VERSION 5.7 ;
BUSBITCHARS "[]" ;
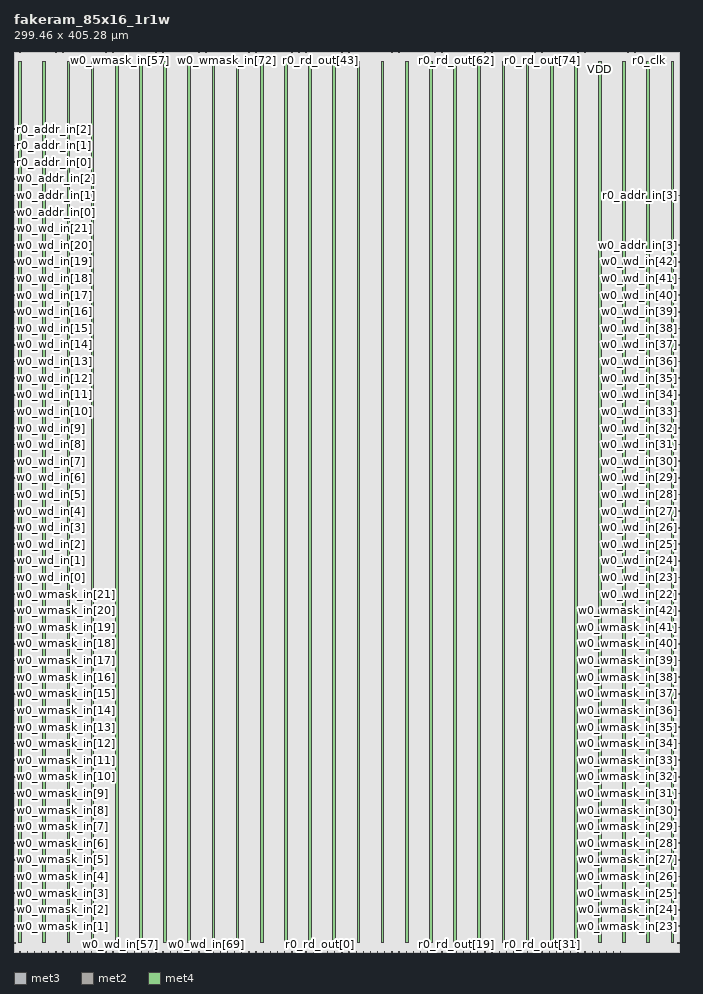
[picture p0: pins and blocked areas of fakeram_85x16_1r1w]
MACRO fakeram_85x16_1r1w
  FOREIGN fakeram_85x16_1r1w 0 0 ;
  SYMMETRY X Y R90 ;
  SIZE 299.460 BY 405.280 ;
  CLASS BLOCK ;
  PIN w0_wmask_in[0]
    DIRECTION INPUT ;
    USE SIGNAL ;
    SHAPE ABUTMENT ;
    PORT
      LAYER met3 ;
      RECT 0.000 3.930 0.900 4.230 ;
    END
  END w0_wmask_in[0]
  PIN w0_wmask_in[1]
    DIRECTION INPUT ;
    USE SIGNAL ;
    SHAPE ABUTMENT ;
    PORT
      LAYER met3 ;
      RECT 0.000 11.410 0.900 11.710 ;
    END
  END w0_wmask_in[1]
  PIN w0_wmask_in[2]
    DIRECTION INPUT ;
    USE SIGNAL ;
    SHAPE ABUTMENT ;
    PORT
      LAYER met3 ;
      RECT 0.000 18.890 0.900 19.190 ;
    END
  END w0_wmask_in[2]
  PIN w0_wmask_in[3]
    DIRECTION INPUT ;
    USE SIGNAL ;
    SHAPE ABUTMENT ;
    PORT
      LAYER met3 ;
      RECT 0.000 26.370 0.900 26.670 ;
    END
  END w0_wmask_in[3]
  PIN w0_wmask_in[4]
    DIRECTION INPUT ;
    USE SIGNAL ;
    SHAPE ABUTMENT ;
    PORT
      LAYER met3 ;
      RECT 0.000 33.850 0.900 34.150 ;
    END
  END w0_wmask_in[4]
  PIN w0_wmask_in[5]
    DIRECTION INPUT ;
    USE SIGNAL ;
    SHAPE ABUTMENT ;
    PORT
      LAYER met3 ;
      RECT 0.000 41.330 0.900 41.630 ;
    END
  END w0_wmask_in[5]
  PIN w0_wmask_in[6]
    DIRECTION INPUT ;
    USE SIGNAL ;
    SHAPE ABUTMENT ;
    PORT
      LAYER met3 ;
      RECT 0.000 48.810 0.900 49.110 ;
    END
  END w0_wmask_in[6]
  PIN w0_wmask_in[7]
    DIRECTION INPUT ;
    USE SIGNAL ;
    SHAPE ABUTMENT ;
    PORT
      LAYER met3 ;
      RECT 0.000 56.290 0.900 56.590 ;
    END
  END w0_wmask_in[7]
  PIN w0_wmask_in[8]
    DIRECTION INPUT ;
    USE SIGNAL ;
    SHAPE ABUTMENT ;
    PORT
      LAYER met3 ;
      RECT 0.000 63.770 0.900 64.070 ;
    END
  END w0_wmask_in[8]
  PIN w0_wmask_in[9]
    DIRECTION INPUT ;
    USE SIGNAL ;
    SHAPE ABUTMENT ;
    PORT
      LAYER met3 ;
      RECT 0.000 71.250 0.900 71.550 ;
    END
  END w0_wmask_in[9]
  PIN w0_wmask_in[10]
    DIRECTION INPUT ;
    USE SIGNAL ;
    SHAPE ABUTMENT ;
    PORT
      LAYER met3 ;
      RECT 0.000 78.730 0.900 79.030 ;
    END
  END w0_wmask_in[10]
  PIN w0_wmask_in[11]
    DIRECTION INPUT ;
    USE SIGNAL ;
    SHAPE ABUTMENT ;
    PORT
      LAYER met3 ;
      RECT 0.000 86.210 0.900 86.510 ;
    END
  END w0_wmask_in[11]
  PIN w0_wmask_in[12]
    DIRECTION INPUT ;
    USE SIGNAL ;
    SHAPE ABUTMENT ;
    PORT
      LAYER met3 ;
      RECT 0.000 93.690 0.900 93.990 ;
    END
  END w0_wmask_in[12]
  PIN w0_wmask_in[13]
    DIRECTION INPUT ;
    USE SIGNAL ;
    SHAPE ABUTMENT ;
    PORT
      LAYER met3 ;
      RECT 0.000 101.170 0.900 101.470 ;
    END
  END w0_wmask_in[13]
  PIN w0_wmask_in[14]
    DIRECTION INPUT ;
    USE SIGNAL ;
    SHAPE ABUTMENT ;
    PORT
      LAYER met3 ;
      RECT 0.000 108.650 0.900 108.950 ;
    END
  END w0_wmask_in[14]
  PIN w0_wmask_in[15]
    DIRECTION INPUT ;
    USE SIGNAL ;
    SHAPE ABUTMENT ;
    PORT
      LAYER met3 ;
      RECT 0.000 116.130 0.900 116.430 ;
    END
  END w0_wmask_in[15]
  PIN w0_wmask_in[16]
    DIRECTION INPUT ;
    USE SIGNAL ;
    SHAPE ABUTMENT ;
    PORT
      LAYER met3 ;
      RECT 0.000 123.610 0.900 123.910 ;
    END
  END w0_wmask_in[16]
  PIN w0_wmask_in[17]
    DIRECTION INPUT ;
    USE SIGNAL ;
    SHAPE ABUTMENT ;
    PORT
      LAYER met3 ;
      RECT 0.000 131.090 0.900 131.390 ;
    END
  END w0_wmask_in[17]
  PIN w0_wmask_in[18]
    DIRECTION INPUT ;
    USE SIGNAL ;
    SHAPE ABUTMENT ;
    PORT
      LAYER met3 ;
      RECT 0.000 138.570 0.900 138.870 ;
    END
  END w0_wmask_in[18]
  PIN w0_wmask_in[19]
    DIRECTION INPUT ;
    USE SIGNAL ;
    SHAPE ABUTMENT ;
    PORT
      LAYER met3 ;
      RECT 0.000 146.050 0.900 146.350 ;
    END
  END w0_wmask_in[19]
  PIN w0_wmask_in[20]
    DIRECTION INPUT ;
    USE SIGNAL ;
    SHAPE ABUTMENT ;
    PORT
      LAYER met3 ;
      RECT 0.000 153.530 0.900 153.830 ;
    END
  END w0_wmask_in[20]
  PIN w0_wmask_in[21]
    DIRECTION INPUT ;
    USE SIGNAL ;
    SHAPE ABUTMENT ;
    PORT
      LAYER met3 ;
      RECT 0.000 161.010 0.900 161.310 ;
    END
  END w0_wmask_in[21]
  PIN w0_wmask_in[22]
    DIRECTION INPUT ;
    USE SIGNAL ;
    SHAPE ABUTMENT ;
    PORT
      LAYER met3 ;
      RECT 298.560 3.930 299.460 4.230 ;
    END
  END w0_wmask_in[22]
  PIN w0_wmask_in[23]
    DIRECTION INPUT ;
    USE SIGNAL ;
    SHAPE ABUTMENT ;
    PORT
      LAYER met3 ;
      RECT 298.560 11.410 299.460 11.710 ;
    END
  END w0_wmask_in[23]
  PIN w0_wmask_in[24]
    DIRECTION INPUT ;
    USE SIGNAL ;
    SHAPE ABUTMENT ;
    PORT
      LAYER met3 ;
      RECT 298.560 18.890 299.460 19.190 ;
    END
  END w0_wmask_in[24]
  PIN w0_wmask_in[25]
    DIRECTION INPUT ;
    USE SIGNAL ;
    SHAPE ABUTMENT ;
    PORT
      LAYER met3 ;
      RECT 298.560 26.370 299.460 26.670 ;
    END
  END w0_wmask_in[25]
  PIN w0_wmask_in[26]
    DIRECTION INPUT ;
    USE SIGNAL ;
    SHAPE ABUTMENT ;
    PORT
      LAYER met3 ;
      RECT 298.560 33.850 299.460 34.150 ;
    END
  END w0_wmask_in[26]
  PIN w0_wmask_in[27]
    DIRECTION INPUT ;
    USE SIGNAL ;
    SHAPE ABUTMENT ;
    PORT
      LAYER met3 ;
      RECT 298.560 41.330 299.460 41.630 ;
    END
  END w0_wmask_in[27]
  PIN w0_wmask_in[28]
    DIRECTION INPUT ;
    USE SIGNAL ;
    SHAPE ABUTMENT ;
    PORT
      LAYER met3 ;
      RECT 298.560 48.810 299.460 49.110 ;
    END
  END w0_wmask_in[28]
  PIN w0_wmask_in[29]
    DIRECTION INPUT ;
    USE SIGNAL ;
    SHAPE ABUTMENT ;
    PORT
      LAYER met3 ;
      RECT 298.560 56.290 299.460 56.590 ;
    END
  END w0_wmask_in[29]
  PIN w0_wmask_in[30]
    DIRECTION INPUT ;
    USE SIGNAL ;
    SHAPE ABUTMENT ;
    PORT
      LAYER met3 ;
      RECT 298.560 63.770 299.460 64.070 ;
    END
  END w0_wmask_in[30]
  PIN w0_wmask_in[31]
    DIRECTION INPUT ;
    USE SIGNAL ;
    SHAPE ABUTMENT ;
    PORT
      LAYER met3 ;
      RECT 298.560 71.250 299.460 71.550 ;
    END
  END w0_wmask_in[31]
  PIN w0_wmask_in[32]
    DIRECTION INPUT ;
    USE SIGNAL ;
    SHAPE ABUTMENT ;
    PORT
      LAYER met3 ;
      RECT 298.560 78.730 299.460 79.030 ;
    END
  END w0_wmask_in[32]
  PIN w0_wmask_in[33]
    DIRECTION INPUT ;
    USE SIGNAL ;
    SHAPE ABUTMENT ;
    PORT
      LAYER met3 ;
      RECT 298.560 86.210 299.460 86.510 ;
    END
  END w0_wmask_in[33]
  PIN w0_wmask_in[34]
    DIRECTION INPUT ;
    USE SIGNAL ;
    SHAPE ABUTMENT ;
    PORT
      LAYER met3 ;
      RECT 298.560 93.690 299.460 93.990 ;
    END
  END w0_wmask_in[34]
  PIN w0_wmask_in[35]
    DIRECTION INPUT ;
    USE SIGNAL ;
    SHAPE ABUTMENT ;
    PORT
      LAYER met3 ;
      RECT 298.560 101.170 299.460 101.470 ;
    END
  END w0_wmask_in[35]
  PIN w0_wmask_in[36]
    DIRECTION INPUT ;
    USE SIGNAL ;
    SHAPE ABUTMENT ;
    PORT
      LAYER met3 ;
      RECT 298.560 108.650 299.460 108.950 ;
    END
  END w0_wmask_in[36]
  PIN w0_wmask_in[37]
    DIRECTION INPUT ;
    USE SIGNAL ;
    SHAPE ABUTMENT ;
    PORT
      LAYER met3 ;
      RECT 298.560 116.130 299.460 116.430 ;
    END
  END w0_wmask_in[37]
  PIN w0_wmask_in[38]
    DIRECTION INPUT ;
    USE SIGNAL ;
    SHAPE ABUTMENT ;
    PORT
      LAYER met3 ;
      RECT 298.560 123.610 299.460 123.910 ;
    END
  END w0_wmask_in[38]
  PIN w0_wmask_in[39]
    DIRECTION INPUT ;
    USE SIGNAL ;
    SHAPE ABUTMENT ;
    PORT
      LAYER met3 ;
      RECT 298.560 131.090 299.460 131.390 ;
    END
  END w0_wmask_in[39]
  PIN w0_wmask_in[40]
    DIRECTION INPUT ;
    USE SIGNAL ;
    SHAPE ABUTMENT ;
    PORT
      LAYER met3 ;
      RECT 298.560 138.570 299.460 138.870 ;
    END
  END w0_wmask_in[40]
  PIN w0_wmask_in[41]
    DIRECTION INPUT ;
    USE SIGNAL ;
    SHAPE ABUTMENT ;
    PORT
      LAYER met3 ;
      RECT 298.560 146.050 299.460 146.350 ;
    END
  END w0_wmask_in[41]
  PIN w0_wmask_in[42]
    DIRECTION INPUT ;
    USE SIGNAL ;
    SHAPE ABUTMENT ;
    PORT
      LAYER met3 ;
      RECT 298.560 153.530 299.460 153.830 ;
    END
  END w0_wmask_in[42]
  PIN w0_wmask_in[43]
    DIRECTION INPUT ;
    USE SIGNAL ;
    SHAPE ABUTMENT ;
    PORT
      LAYER met2 ;
      RECT 2.690 404.860 2.830 405.280 ;
    END
  END w0_wmask_in[43]
  PIN w0_wmask_in[44]
    DIRECTION INPUT ;
    USE SIGNAL ;
    SHAPE ABUTMENT ;
    PORT
      LAYER met2 ;
      RECT 5.910 404.860 6.050 405.280 ;
    END
  END w0_wmask_in[44]
  PIN w0_wmask_in[45]
    DIRECTION INPUT ;
    USE SIGNAL ;
    SHAPE ABUTMENT ;
    PORT
      LAYER met2 ;
      RECT 9.130 404.860 9.270 405.280 ;
    END
  END w0_wmask_in[45]
  PIN w0_wmask_in[46]
    DIRECTION INPUT ;
    USE SIGNAL ;
    SHAPE ABUTMENT ;
    PORT
      LAYER met2 ;
      RECT 12.350 404.860 12.490 405.280 ;
    END
  END w0_wmask_in[46]
  PIN w0_wmask_in[47]
    DIRECTION INPUT ;
    USE SIGNAL ;
    SHAPE ABUTMENT ;
    PORT
      LAYER met2 ;
      RECT 15.570 404.860 15.710 405.280 ;
    END
  END w0_wmask_in[47]
  PIN w0_wmask_in[48]
    DIRECTION INPUT ;
    USE SIGNAL ;
    SHAPE ABUTMENT ;
    PORT
      LAYER met2 ;
      RECT 18.790 404.860 18.930 405.280 ;
    END
  END w0_wmask_in[48]
  PIN w0_wmask_in[49]
    DIRECTION INPUT ;
    USE SIGNAL ;
    SHAPE ABUTMENT ;
    PORT
      LAYER met2 ;
      RECT 22.010 404.860 22.150 405.280 ;
    END
  END w0_wmask_in[49]
  PIN w0_wmask_in[50]
    DIRECTION INPUT ;
    USE SIGNAL ;
    SHAPE ABUTMENT ;
    PORT
      LAYER met2 ;
      RECT 25.230 404.860 25.370 405.280 ;
    END
  END w0_wmask_in[50]
  PIN w0_wmask_in[51]
    DIRECTION INPUT ;
    USE SIGNAL ;
    SHAPE ABUTMENT ;
    PORT
      LAYER met2 ;
      RECT 28.450 404.860 28.590 405.280 ;
    END
  END w0_wmask_in[51]
  PIN w0_wmask_in[52]
    DIRECTION INPUT ;
    USE SIGNAL ;
    SHAPE ABUTMENT ;
    PORT
      LAYER met2 ;
      RECT 31.670 404.860 31.810 405.280 ;
    END
  END w0_wmask_in[52]
  PIN w0_wmask_in[53]
    DIRECTION INPUT ;
    USE SIGNAL ;
    SHAPE ABUTMENT ;
    PORT
      LAYER met2 ;
      RECT 34.890 404.860 35.030 405.280 ;
    END
  END w0_wmask_in[53]
  PIN w0_wmask_in[54]
    DIRECTION INPUT ;
    USE SIGNAL ;
    SHAPE ABUTMENT ;
    PORT
      LAYER met2 ;
      RECT 38.110 404.860 38.250 405.280 ;
    END
  END w0_wmask_in[54]
  PIN w0_wmask_in[55]
    DIRECTION INPUT ;
    USE SIGNAL ;
    SHAPE ABUTMENT ;
    PORT
      LAYER met2 ;
      RECT 41.330 404.860 41.470 405.280 ;
    END
  END w0_wmask_in[55]
  PIN w0_wmask_in[56]
    DIRECTION INPUT ;
    USE SIGNAL ;
    SHAPE ABUTMENT ;
    PORT
      LAYER met2 ;
      RECT 44.550 404.860 44.690 405.280 ;
    END
  END w0_wmask_in[56]
  PIN w0_wmask_in[57]
    DIRECTION INPUT ;
    USE SIGNAL ;
    SHAPE ABUTMENT ;
    PORT
      LAYER met2 ;
      RECT 47.770 404.860 47.910 405.280 ;
    END
  END w0_wmask_in[57]
  PIN w0_wmask_in[58]
    DIRECTION INPUT ;
    USE SIGNAL ;
    SHAPE ABUTMENT ;
    PORT
      LAYER met2 ;
      RECT 50.990 404.860 51.130 405.280 ;
    END
  END w0_wmask_in[58]
  PIN w0_wmask_in[59]
    DIRECTION INPUT ;
    USE SIGNAL ;
    SHAPE ABUTMENT ;
    PORT
      LAYER met2 ;
      RECT 54.210 404.860 54.350 405.280 ;
    END
  END w0_wmask_in[59]
  PIN w0_wmask_in[60]
    DIRECTION INPUT ;
    USE SIGNAL ;
    SHAPE ABUTMENT ;
    PORT
      LAYER met2 ;
      RECT 57.430 404.860 57.570 405.280 ;
    END
  END w0_wmask_in[60]
  PIN w0_wmask_in[61]
    DIRECTION INPUT ;
    USE SIGNAL ;
    SHAPE ABUTMENT ;
    PORT
      LAYER met2 ;
      RECT 60.650 404.860 60.790 405.280 ;
    END
  END w0_wmask_in[61]
  PIN w0_wmask_in[62]
    DIRECTION INPUT ;
    USE SIGNAL ;
    SHAPE ABUTMENT ;
    PORT
      LAYER met2 ;
      RECT 63.870 404.860 64.010 405.280 ;
    END
  END w0_wmask_in[62]
  PIN w0_wmask_in[63]
    DIRECTION INPUT ;
    USE SIGNAL ;
    SHAPE ABUTMENT ;
    PORT
      LAYER met2 ;
      RECT 67.090 404.860 67.230 405.280 ;
    END
  END w0_wmask_in[63]
  PIN w0_wmask_in[64]
    DIRECTION INPUT ;
    USE SIGNAL ;
    SHAPE ABUTMENT ;
    PORT
      LAYER met2 ;
      RECT 70.310 404.860 70.450 405.280 ;
    END
  END w0_wmask_in[64]
  PIN w0_wmask_in[65]
    DIRECTION INPUT ;
    USE SIGNAL ;
    SHAPE ABUTMENT ;
    PORT
      LAYER met2 ;
      RECT 73.530 404.860 73.670 405.280 ;
    END
  END w0_wmask_in[65]
  PIN w0_wmask_in[66]
    DIRECTION INPUT ;
    USE SIGNAL ;
    SHAPE ABUTMENT ;
    PORT
      LAYER met2 ;
      RECT 76.750 404.860 76.890 405.280 ;
    END
  END w0_wmask_in[66]
  PIN w0_wmask_in[67]
    DIRECTION INPUT ;
    USE SIGNAL ;
    SHAPE ABUTMENT ;
    PORT
      LAYER met2 ;
      RECT 79.970 404.860 80.110 405.280 ;
    END
  END w0_wmask_in[67]
  PIN w0_wmask_in[68]
    DIRECTION INPUT ;
    USE SIGNAL ;
    SHAPE ABUTMENT ;
    PORT
      LAYER met2 ;
      RECT 83.190 404.860 83.330 405.280 ;
    END
  END w0_wmask_in[68]
  PIN w0_wmask_in[69]
    DIRECTION INPUT ;
    USE SIGNAL ;
    SHAPE ABUTMENT ;
    PORT
      LAYER met2 ;
      RECT 86.410 404.860 86.550 405.280 ;
    END
  END w0_wmask_in[69]
  PIN w0_wmask_in[70]
    DIRECTION INPUT ;
    USE SIGNAL ;
    SHAPE ABUTMENT ;
    PORT
      LAYER met2 ;
      RECT 89.630 404.860 89.770 405.280 ;
    END
  END w0_wmask_in[70]
  PIN w0_wmask_in[71]
    DIRECTION INPUT ;
    USE SIGNAL ;
    SHAPE ABUTMENT ;
    PORT
      LAYER met2 ;
      RECT 92.850 404.860 92.990 405.280 ;
    END
  END w0_wmask_in[71]
  PIN w0_wmask_in[72]
    DIRECTION INPUT ;
    USE SIGNAL ;
    SHAPE ABUTMENT ;
    PORT
      LAYER met2 ;
      RECT 96.070 404.860 96.210 405.280 ;
    END
  END w0_wmask_in[72]
  PIN w0_wmask_in[73]
    DIRECTION INPUT ;
    USE SIGNAL ;
    SHAPE ABUTMENT ;
    PORT
      LAYER met2 ;
      RECT 99.290 404.860 99.430 405.280 ;
    END
  END w0_wmask_in[73]
  PIN w0_wmask_in[74]
    DIRECTION INPUT ;
    USE SIGNAL ;
    SHAPE ABUTMENT ;
    PORT
      LAYER met2 ;
      RECT 102.510 404.860 102.650 405.280 ;
    END
  END w0_wmask_in[74]
  PIN w0_wmask_in[75]
    DIRECTION INPUT ;
    USE SIGNAL ;
    SHAPE ABUTMENT ;
    PORT
      LAYER met2 ;
      RECT 105.730 404.860 105.870 405.280 ;
    END
  END w0_wmask_in[75]
  PIN w0_wmask_in[76]
    DIRECTION INPUT ;
    USE SIGNAL ;
    SHAPE ABUTMENT ;
    PORT
      LAYER met2 ;
      RECT 108.950 404.860 109.090 405.280 ;
    END
  END w0_wmask_in[76]
  PIN w0_wmask_in[77]
    DIRECTION INPUT ;
    USE SIGNAL ;
    SHAPE ABUTMENT ;
    PORT
      LAYER met2 ;
      RECT 112.170 404.860 112.310 405.280 ;
    END
  END w0_wmask_in[77]
  PIN w0_wmask_in[78]
    DIRECTION INPUT ;
    USE SIGNAL ;
    SHAPE ABUTMENT ;
    PORT
      LAYER met2 ;
      RECT 115.390 404.860 115.530 405.280 ;
    END
  END w0_wmask_in[78]
  PIN w0_wmask_in[79]
    DIRECTION INPUT ;
    USE SIGNAL ;
    SHAPE ABUTMENT ;
    PORT
      LAYER met2 ;
      RECT 118.610 404.860 118.750 405.280 ;
    END
  END w0_wmask_in[79]
  PIN w0_wmask_in[80]
    DIRECTION INPUT ;
    USE SIGNAL ;
    SHAPE ABUTMENT ;
    PORT
      LAYER met2 ;
      RECT 121.830 404.860 121.970 405.280 ;
    END
  END w0_wmask_in[80]
  PIN w0_wmask_in[81]
    DIRECTION INPUT ;
    USE SIGNAL ;
    SHAPE ABUTMENT ;
    PORT
      LAYER met2 ;
      RECT 125.050 404.860 125.190 405.280 ;
    END
  END w0_wmask_in[81]
  PIN w0_wmask_in[82]
    DIRECTION INPUT ;
    USE SIGNAL ;
    SHAPE ABUTMENT ;
    PORT
      LAYER met2 ;
      RECT 128.270 404.860 128.410 405.280 ;
    END
  END w0_wmask_in[82]
  PIN w0_wmask_in[83]
    DIRECTION INPUT ;
    USE SIGNAL ;
    SHAPE ABUTMENT ;
    PORT
      LAYER met2 ;
      RECT 131.490 404.860 131.630 405.280 ;
    END
  END w0_wmask_in[83]
  PIN w0_wmask_in[84]
    DIRECTION INPUT ;
    USE SIGNAL ;
    SHAPE ABUTMENT ;
    PORT
      LAYER met2 ;
      RECT 134.710 404.860 134.850 405.280 ;
    END
  END w0_wmask_in[84]
  PIN w0_wd_in[0]
    DIRECTION INPUT ;
    USE SIGNAL ;
    SHAPE ABUTMENT ;
    PORT
      LAYER met3 ;
      RECT 0.000 168.490 0.900 168.790 ;
    END
  END w0_wd_in[0]
  PIN w0_wd_in[1]
    DIRECTION INPUT ;
    USE SIGNAL ;
    SHAPE ABUTMENT ;
    PORT
      LAYER met3 ;
      RECT 0.000 175.970 0.900 176.270 ;
    END
  END w0_wd_in[1]
  PIN w0_wd_in[2]
    DIRECTION INPUT ;
    USE SIGNAL ;
    SHAPE ABUTMENT ;
    PORT
      LAYER met3 ;
      RECT 0.000 183.450 0.900 183.750 ;
    END
  END w0_wd_in[2]
  PIN w0_wd_in[3]
    DIRECTION INPUT ;
    USE SIGNAL ;
    SHAPE ABUTMENT ;
    PORT
      LAYER met3 ;
      RECT 0.000 190.930 0.900 191.230 ;
    END
  END w0_wd_in[3]
  PIN w0_wd_in[4]
    DIRECTION INPUT ;
    USE SIGNAL ;
    SHAPE ABUTMENT ;
    PORT
      LAYER met3 ;
      RECT 0.000 198.410 0.900 198.710 ;
    END
  END w0_wd_in[4]
  PIN w0_wd_in[5]
    DIRECTION INPUT ;
    USE SIGNAL ;
    SHAPE ABUTMENT ;
    PORT
      LAYER met3 ;
      RECT 0.000 205.890 0.900 206.190 ;
    END
  END w0_wd_in[5]
  PIN w0_wd_in[6]
    DIRECTION INPUT ;
    USE SIGNAL ;
    SHAPE ABUTMENT ;
    PORT
      LAYER met3 ;
      RECT 0.000 213.370 0.900 213.670 ;
    END
  END w0_wd_in[6]
  PIN w0_wd_in[7]
    DIRECTION INPUT ;
    USE SIGNAL ;
    SHAPE ABUTMENT ;
    PORT
      LAYER met3 ;
      RECT 0.000 220.850 0.900 221.150 ;
    END
  END w0_wd_in[7]
  PIN w0_wd_in[8]
    DIRECTION INPUT ;
    USE SIGNAL ;
    SHAPE ABUTMENT ;
    PORT
      LAYER met3 ;
      RECT 0.000 228.330 0.900 228.630 ;
    END
  END w0_wd_in[8]
  PIN w0_wd_in[9]
    DIRECTION INPUT ;
    USE SIGNAL ;
    SHAPE ABUTMENT ;
    PORT
      LAYER met3 ;
      RECT 0.000 235.810 0.900 236.110 ;
    END
  END w0_wd_in[9]
  PIN w0_wd_in[10]
    DIRECTION INPUT ;
    USE SIGNAL ;
    SHAPE ABUTMENT ;
    PORT
      LAYER met3 ;
      RECT 0.000 243.290 0.900 243.590 ;
    END
  END w0_wd_in[10]
  PIN w0_wd_in[11]
    DIRECTION INPUT ;
    USE SIGNAL ;
    SHAPE ABUTMENT ;
    PORT
      LAYER met3 ;
      RECT 0.000 250.770 0.900 251.070 ;
    END
  END w0_wd_in[11]
  PIN w0_wd_in[12]
    DIRECTION INPUT ;
    USE SIGNAL ;
    SHAPE ABUTMENT ;
    PORT
      LAYER met3 ;
      RECT 0.000 258.250 0.900 258.550 ;
    END
  END w0_wd_in[12]
  PIN w0_wd_in[13]
    DIRECTION INPUT ;
    USE SIGNAL ;
    SHAPE ABUTMENT ;
    PORT
      LAYER met3 ;
      RECT 0.000 265.730 0.900 266.030 ;
    END
  END w0_wd_in[13]
  PIN w0_wd_in[14]
    DIRECTION INPUT ;
    USE SIGNAL ;
    SHAPE ABUTMENT ;
    PORT
      LAYER met3 ;
      RECT 0.000 273.210 0.900 273.510 ;
    END
  END w0_wd_in[14]
  PIN w0_wd_in[15]
    DIRECTION INPUT ;
    USE SIGNAL ;
    SHAPE ABUTMENT ;
    PORT
      LAYER met3 ;
      RECT 0.000 280.690 0.900 280.990 ;
    END
  END w0_wd_in[15]
  PIN w0_wd_in[16]
    DIRECTION INPUT ;
    USE SIGNAL ;
    SHAPE ABUTMENT ;
    PORT
      LAYER met3 ;
      RECT 0.000 288.170 0.900 288.470 ;
    END
  END w0_wd_in[16]
  PIN w0_wd_in[17]
    DIRECTION INPUT ;
    USE SIGNAL ;
    SHAPE ABUTMENT ;
    PORT
      LAYER met3 ;
      RECT 0.000 295.650 0.900 295.950 ;
    END
  END w0_wd_in[17]
  PIN w0_wd_in[18]
    DIRECTION INPUT ;
    USE SIGNAL ;
    SHAPE ABUTMENT ;
    PORT
      LAYER met3 ;
      RECT 0.000 303.130 0.900 303.430 ;
    END
  END w0_wd_in[18]
  PIN w0_wd_in[19]
    DIRECTION INPUT ;
    USE SIGNAL ;
    SHAPE ABUTMENT ;
    PORT
      LAYER met3 ;
      RECT 0.000 310.610 0.900 310.910 ;
    END
  END w0_wd_in[19]
  PIN w0_wd_in[20]
    DIRECTION INPUT ;
    USE SIGNAL ;
    SHAPE ABUTMENT ;
    PORT
      LAYER met3 ;
      RECT 0.000 318.090 0.900 318.390 ;
    END
  END w0_wd_in[20]
  PIN w0_wd_in[21]
    DIRECTION INPUT ;
    USE SIGNAL ;
    SHAPE ABUTMENT ;
    PORT
      LAYER met3 ;
      RECT 0.000 325.570 0.900 325.870 ;
    END
  END w0_wd_in[21]
  PIN w0_wd_in[22]
    DIRECTION INPUT ;
    USE SIGNAL ;
    SHAPE ABUTMENT ;
    PORT
      LAYER met3 ;
      RECT 298.560 161.010 299.460 161.310 ;
    END
  END w0_wd_in[22]
  PIN w0_wd_in[23]
    DIRECTION INPUT ;
    USE SIGNAL ;
    SHAPE ABUTMENT ;
    PORT
      LAYER met3 ;
      RECT 298.560 168.490 299.460 168.790 ;
    END
  END w0_wd_in[23]
  PIN w0_wd_in[24]
    DIRECTION INPUT ;
    USE SIGNAL ;
    SHAPE ABUTMENT ;
    PORT
      LAYER met3 ;
      RECT 298.560 175.970 299.460 176.270 ;
    END
  END w0_wd_in[24]
  PIN w0_wd_in[25]
    DIRECTION INPUT ;
    USE SIGNAL ;
    SHAPE ABUTMENT ;
    PORT
      LAYER met3 ;
      RECT 298.560 183.450 299.460 183.750 ;
    END
  END w0_wd_in[25]
  PIN w0_wd_in[26]
    DIRECTION INPUT ;
    USE SIGNAL ;
    SHAPE ABUTMENT ;
    PORT
      LAYER met3 ;
      RECT 298.560 190.930 299.460 191.230 ;
    END
  END w0_wd_in[26]
  PIN w0_wd_in[27]
    DIRECTION INPUT ;
    USE SIGNAL ;
    SHAPE ABUTMENT ;
    PORT
      LAYER met3 ;
      RECT 298.560 198.410 299.460 198.710 ;
    END
  END w0_wd_in[27]
  PIN w0_wd_in[28]
    DIRECTION INPUT ;
    USE SIGNAL ;
    SHAPE ABUTMENT ;
    PORT
      LAYER met3 ;
      RECT 298.560 205.890 299.460 206.190 ;
    END
  END w0_wd_in[28]
  PIN w0_wd_in[29]
    DIRECTION INPUT ;
    USE SIGNAL ;
    SHAPE ABUTMENT ;
    PORT
      LAYER met3 ;
      RECT 298.560 213.370 299.460 213.670 ;
    END
  END w0_wd_in[29]
  PIN w0_wd_in[30]
    DIRECTION INPUT ;
    USE SIGNAL ;
    SHAPE ABUTMENT ;
    PORT
      LAYER met3 ;
      RECT 298.560 220.850 299.460 221.150 ;
    END
  END w0_wd_in[30]
  PIN w0_wd_in[31]
    DIRECTION INPUT ;
    USE SIGNAL ;
    SHAPE ABUTMENT ;
    PORT
      LAYER met3 ;
      RECT 298.560 228.330 299.460 228.630 ;
    END
  END w0_wd_in[31]
  PIN w0_wd_in[32]
    DIRECTION INPUT ;
    USE SIGNAL ;
    SHAPE ABUTMENT ;
    PORT
      LAYER met3 ;
      RECT 298.560 235.810 299.460 236.110 ;
    END
  END w0_wd_in[32]
  PIN w0_wd_in[33]
    DIRECTION INPUT ;
    USE SIGNAL ;
    SHAPE ABUTMENT ;
    PORT
      LAYER met3 ;
      RECT 298.560 243.290 299.460 243.590 ;
    END
  END w0_wd_in[33]
  PIN w0_wd_in[34]
    DIRECTION INPUT ;
    USE SIGNAL ;
    SHAPE ABUTMENT ;
    PORT
      LAYER met3 ;
      RECT 298.560 250.770 299.460 251.070 ;
    END
  END w0_wd_in[34]
  PIN w0_wd_in[35]
    DIRECTION INPUT ;
    USE SIGNAL ;
    SHAPE ABUTMENT ;
    PORT
      LAYER met3 ;
      RECT 298.560 258.250 299.460 258.550 ;
    END
  END w0_wd_in[35]
  PIN w0_wd_in[36]
    DIRECTION INPUT ;
    USE SIGNAL ;
    SHAPE ABUTMENT ;
    PORT
      LAYER met3 ;
      RECT 298.560 265.730 299.460 266.030 ;
    END
  END w0_wd_in[36]
  PIN w0_wd_in[37]
    DIRECTION INPUT ;
    USE SIGNAL ;
    SHAPE ABUTMENT ;
    PORT
      LAYER met3 ;
      RECT 298.560 273.210 299.460 273.510 ;
    END
  END w0_wd_in[37]
  PIN w0_wd_in[38]
    DIRECTION INPUT ;
    USE SIGNAL ;
    SHAPE ABUTMENT ;
    PORT
      LAYER met3 ;
      RECT 298.560 280.690 299.460 280.990 ;
    END
  END w0_wd_in[38]
  PIN w0_wd_in[39]
    DIRECTION INPUT ;
    USE SIGNAL ;
    SHAPE ABUTMENT ;
    PORT
      LAYER met3 ;
      RECT 298.560 288.170 299.460 288.470 ;
    END
  END w0_wd_in[39]
  PIN w0_wd_in[40]
    DIRECTION INPUT ;
    USE SIGNAL ;
    SHAPE ABUTMENT ;
    PORT
      LAYER met3 ;
      RECT 298.560 295.650 299.460 295.950 ;
    END
  END w0_wd_in[40]
  PIN w0_wd_in[41]
    DIRECTION INPUT ;
    USE SIGNAL ;
    SHAPE ABUTMENT ;
    PORT
      LAYER met3 ;
      RECT 298.560 303.130 299.460 303.430 ;
    END
  END w0_wd_in[41]
  PIN w0_wd_in[42]
    DIRECTION INPUT ;
    USE SIGNAL ;
    SHAPE ABUTMENT ;
    PORT
      LAYER met3 ;
      RECT 298.560 310.610 299.460 310.910 ;
    END
  END w0_wd_in[42]
  PIN w0_wd_in[43]
    DIRECTION OUTPUT ;
    USE SIGNAL ;
    SHAPE ABUTMENT ;
    PORT
      LAYER met2 ;
      RECT 2.690 0.000 2.830 0.420 ;
    END
  END w0_wd_in[43]
  PIN w0_wd_in[44]
    DIRECTION OUTPUT ;
    USE SIGNAL ;
    SHAPE ABUTMENT ;
    PORT
      LAYER met2 ;
      RECT 5.910 0.000 6.050 0.420 ;
    END
  END w0_wd_in[44]
  PIN w0_wd_in[45]
    DIRECTION OUTPUT ;
    USE SIGNAL ;
    SHAPE ABUTMENT ;
    PORT
      LAYER met2 ;
      RECT 9.130 0.000 9.270 0.420 ;
    END
  END w0_wd_in[45]
  PIN w0_wd_in[46]
    DIRECTION OUTPUT ;
    USE SIGNAL ;
    SHAPE ABUTMENT ;
    PORT
      LAYER met2 ;
      RECT 12.350 0.000 12.490 0.420 ;
    END
  END w0_wd_in[46]
  PIN w0_wd_in[47]
    DIRECTION OUTPUT ;
    USE SIGNAL ;
    SHAPE ABUTMENT ;
    PORT
      LAYER met2 ;
      RECT 15.570 0.000 15.710 0.420 ;
    END
  END w0_wd_in[47]
  PIN w0_wd_in[48]
    DIRECTION OUTPUT ;
    USE SIGNAL ;
    SHAPE ABUTMENT ;
    PORT
      LAYER met2 ;
      RECT 18.790 0.000 18.930 0.420 ;
    END
  END w0_wd_in[48]
  PIN w0_wd_in[49]
    DIRECTION OUTPUT ;
    USE SIGNAL ;
    SHAPE ABUTMENT ;
    PORT
      LAYER met2 ;
      RECT 22.010 0.000 22.150 0.420 ;
    END
  END w0_wd_in[49]
  PIN w0_wd_in[50]
    DIRECTION OUTPUT ;
    USE SIGNAL ;
    SHAPE ABUTMENT ;
    PORT
      LAYER met2 ;
      RECT 25.230 0.000 25.370 0.420 ;
    END
  END w0_wd_in[50]
  PIN w0_wd_in[51]
    DIRECTION OUTPUT ;
    USE SIGNAL ;
    SHAPE ABUTMENT ;
    PORT
      LAYER met2 ;
      RECT 28.450 0.000 28.590 0.420 ;
    END
  END w0_wd_in[51]
  PIN w0_wd_in[52]
    DIRECTION OUTPUT ;
    USE SIGNAL ;
    SHAPE ABUTMENT ;
    PORT
      LAYER met2 ;
      RECT 31.670 0.000 31.810 0.420 ;
    END
  END w0_wd_in[52]
  PIN w0_wd_in[53]
    DIRECTION OUTPUT ;
    USE SIGNAL ;
    SHAPE ABUTMENT ;
    PORT
      LAYER met2 ;
      RECT 34.890 0.000 35.030 0.420 ;
    END
  END w0_wd_in[53]
  PIN w0_wd_in[54]
    DIRECTION OUTPUT ;
    USE SIGNAL ;
    SHAPE ABUTMENT ;
    PORT
      LAYER met2 ;
      RECT 38.110 0.000 38.250 0.420 ;
    END
  END w0_wd_in[54]
  PIN w0_wd_in[55]
    DIRECTION OUTPUT ;
    USE SIGNAL ;
    SHAPE ABUTMENT ;
    PORT
      LAYER met2 ;
      RECT 41.330 0.000 41.470 0.420 ;
    END
  END w0_wd_in[55]
  PIN w0_wd_in[56]
    DIRECTION OUTPUT ;
    USE SIGNAL ;
    SHAPE ABUTMENT ;
    PORT
      LAYER met2 ;
      RECT 44.550 0.000 44.690 0.420 ;
    END
  END w0_wd_in[56]
  PIN w0_wd_in[57]
    DIRECTION OUTPUT ;
    USE SIGNAL ;
    SHAPE ABUTMENT ;
    PORT
      LAYER met2 ;
      RECT 47.770 0.000 47.910 0.420 ;
    END
  END w0_wd_in[57]
  PIN w0_wd_in[58]
    DIRECTION OUTPUT ;
    USE SIGNAL ;
    SHAPE ABUTMENT ;
    PORT
      LAYER met2 ;
      RECT 50.990 0.000 51.130 0.420 ;
    END
  END w0_wd_in[58]
  PIN w0_wd_in[59]
    DIRECTION OUTPUT ;
    USE SIGNAL ;
    SHAPE ABUTMENT ;
    PORT
      LAYER met2 ;
      RECT 54.210 0.000 54.350 0.420 ;
    END
  END w0_wd_in[59]
  PIN w0_wd_in[60]
    DIRECTION OUTPUT ;
    USE SIGNAL ;
    SHAPE ABUTMENT ;
    PORT
      LAYER met2 ;
      RECT 57.430 0.000 57.570 0.420 ;
    END
  END w0_wd_in[60]
  PIN w0_wd_in[61]
    DIRECTION OUTPUT ;
    USE SIGNAL ;
    SHAPE ABUTMENT ;
    PORT
      LAYER met2 ;
      RECT 60.650 0.000 60.790 0.420 ;
    END
  END w0_wd_in[61]
  PIN w0_wd_in[62]
    DIRECTION OUTPUT ;
    USE SIGNAL ;
    SHAPE ABUTMENT ;
    PORT
      LAYER met2 ;
      RECT 63.870 0.000 64.010 0.420 ;
    END
  END w0_wd_in[62]
  PIN w0_wd_in[63]
    DIRECTION OUTPUT ;
    USE SIGNAL ;
    SHAPE ABUTMENT ;
    PORT
      LAYER met2 ;
      RECT 67.090 0.000 67.230 0.420 ;
    END
  END w0_wd_in[63]
  PIN w0_wd_in[64]
    DIRECTION OUTPUT ;
    USE SIGNAL ;
    SHAPE ABUTMENT ;
    PORT
      LAYER met2 ;
      RECT 70.310 0.000 70.450 0.420 ;
    END
  END w0_wd_in[64]
  PIN w0_wd_in[65]
    DIRECTION OUTPUT ;
    USE SIGNAL ;
    SHAPE ABUTMENT ;
    PORT
      LAYER met2 ;
      RECT 73.530 0.000 73.670 0.420 ;
    END
  END w0_wd_in[65]
  PIN w0_wd_in[66]
    DIRECTION OUTPUT ;
    USE SIGNAL ;
    SHAPE ABUTMENT ;
    PORT
      LAYER met2 ;
      RECT 76.750 0.000 76.890 0.420 ;
    END
  END w0_wd_in[66]
  PIN w0_wd_in[67]
    DIRECTION OUTPUT ;
    USE SIGNAL ;
    SHAPE ABUTMENT ;
    PORT
      LAYER met2 ;
      RECT 79.970 0.000 80.110 0.420 ;
    END
  END w0_wd_in[67]
  PIN w0_wd_in[68]
    DIRECTION OUTPUT ;
    USE SIGNAL ;
    SHAPE ABUTMENT ;
    PORT
      LAYER met2 ;
      RECT 83.190 0.000 83.330 0.420 ;
    END
  END w0_wd_in[68]
  PIN w0_wd_in[69]
    DIRECTION OUTPUT ;
    USE SIGNAL ;
    SHAPE ABUTMENT ;
    PORT
      LAYER met2 ;
      RECT 86.410 0.000 86.550 0.420 ;
    END
  END w0_wd_in[69]
  PIN w0_wd_in[70]
    DIRECTION OUTPUT ;
    USE SIGNAL ;
    SHAPE ABUTMENT ;
    PORT
      LAYER met2 ;
      RECT 89.630 0.000 89.770 0.420 ;
    END
  END w0_wd_in[70]
  PIN w0_wd_in[71]
    DIRECTION OUTPUT ;
    USE SIGNAL ;
    SHAPE ABUTMENT ;
    PORT
      LAYER met2 ;
      RECT 92.850 0.000 92.990 0.420 ;
    END
  END w0_wd_in[71]
  PIN w0_wd_in[72]
    DIRECTION OUTPUT ;
    USE SIGNAL ;
    SHAPE ABUTMENT ;
    PORT
      LAYER met2 ;
      RECT 96.070 0.000 96.210 0.420 ;
    END
  END w0_wd_in[72]
  PIN w0_wd_in[73]
    DIRECTION OUTPUT ;
    USE SIGNAL ;
    SHAPE ABUTMENT ;
    PORT
      LAYER met2 ;
      RECT 99.290 0.000 99.430 0.420 ;
    END
  END w0_wd_in[73]
  PIN w0_wd_in[74]
    DIRECTION OUTPUT ;
    USE SIGNAL ;
    SHAPE ABUTMENT ;
    PORT
      LAYER met2 ;
      RECT 102.510 0.000 102.650 0.420 ;
    END
  END w0_wd_in[74]
  PIN w0_wd_in[75]
    DIRECTION OUTPUT ;
    USE SIGNAL ;
    SHAPE ABUTMENT ;
    PORT
      LAYER met2 ;
      RECT 105.730 0.000 105.870 0.420 ;
    END
  END w0_wd_in[75]
  PIN w0_wd_in[76]
    DIRECTION OUTPUT ;
    USE SIGNAL ;
    SHAPE ABUTMENT ;
    PORT
      LAYER met2 ;
      RECT 108.950 0.000 109.090 0.420 ;
    END
  END w0_wd_in[76]
  PIN w0_wd_in[77]
    DIRECTION OUTPUT ;
    USE SIGNAL ;
    SHAPE ABUTMENT ;
    PORT
      LAYER met2 ;
      RECT 112.170 0.000 112.310 0.420 ;
    END
  END w0_wd_in[77]
  PIN w0_wd_in[78]
    DIRECTION OUTPUT ;
    USE SIGNAL ;
    SHAPE ABUTMENT ;
    PORT
      LAYER met2 ;
      RECT 115.390 0.000 115.530 0.420 ;
    END
  END w0_wd_in[78]
  PIN w0_wd_in[79]
    DIRECTION OUTPUT ;
    USE SIGNAL ;
    SHAPE ABUTMENT ;
    PORT
      LAYER met2 ;
      RECT 118.610 0.000 118.750 0.420 ;
    END
  END w0_wd_in[79]
  PIN w0_wd_in[80]
    DIRECTION OUTPUT ;
    USE SIGNAL ;
    SHAPE ABUTMENT ;
    PORT
      LAYER met2 ;
      RECT 121.830 0.000 121.970 0.420 ;
    END
  END w0_wd_in[80]
  PIN w0_wd_in[81]
    DIRECTION OUTPUT ;
    USE SIGNAL ;
    SHAPE ABUTMENT ;
    PORT
      LAYER met2 ;
      RECT 125.050 0.000 125.190 0.420 ;
    END
  END w0_wd_in[81]
  PIN w0_wd_in[82]
    DIRECTION OUTPUT ;
    USE SIGNAL ;
    SHAPE ABUTMENT ;
    PORT
      LAYER met2 ;
      RECT 128.270 0.000 128.410 0.420 ;
    END
  END w0_wd_in[82]
  PIN w0_wd_in[83]
    DIRECTION OUTPUT ;
    USE SIGNAL ;
    SHAPE ABUTMENT ;
    PORT
      LAYER met2 ;
      RECT 131.490 0.000 131.630 0.420 ;
    END
  END w0_wd_in[83]
  PIN w0_wd_in[84]
    DIRECTION OUTPUT ;
    USE SIGNAL ;
    SHAPE ABUTMENT ;
    PORT
      LAYER met2 ;
      RECT 134.710 0.000 134.850 0.420 ;
    END
  END w0_wd_in[84]
  PIN r0_rd_out[0]
    DIRECTION OUTPUT ;
    USE SIGNAL ;
    SHAPE ABUTMENT ;
    PORT
      LAYER met2 ;
      RECT 137.930 0.000 138.070 0.420 ;
    END
  END r0_rd_out[0]
  PIN r0_rd_out[1]
    DIRECTION OUTPUT ;
    USE SIGNAL ;
    SHAPE ABUTMENT ;
    PORT
      LAYER met2 ;
      RECT 141.150 0.000 141.290 0.420 ;
    END
  END r0_rd_out[1]
  PIN r0_rd_out[2]
    DIRECTION OUTPUT ;
    USE SIGNAL ;
    SHAPE ABUTMENT ;
    PORT
      LAYER met2 ;
      RECT 144.370 0.000 144.510 0.420 ;
    END
  END r0_rd_out[2]
  PIN r0_rd_out[3]
    DIRECTION OUTPUT ;
    USE SIGNAL ;
    SHAPE ABUTMENT ;
    PORT
      LAYER met2 ;
      RECT 147.590 0.000 147.730 0.420 ;
    END
  END r0_rd_out[3]
  PIN r0_rd_out[4]
    DIRECTION OUTPUT ;
    USE SIGNAL ;
    SHAPE ABUTMENT ;
    PORT
      LAYER met2 ;
      RECT 150.810 0.000 150.950 0.420 ;
    END
  END r0_rd_out[4]
  PIN r0_rd_out[5]
    DIRECTION OUTPUT ;
    USE SIGNAL ;
    SHAPE ABUTMENT ;
    PORT
      LAYER met2 ;
      RECT 154.030 0.000 154.170 0.420 ;
    END
  END r0_rd_out[5]
  PIN r0_rd_out[6]
    DIRECTION OUTPUT ;
    USE SIGNAL ;
    SHAPE ABUTMENT ;
    PORT
      LAYER met2 ;
      RECT 157.250 0.000 157.390 0.420 ;
    END
  END r0_rd_out[6]
  PIN r0_rd_out[7]
    DIRECTION OUTPUT ;
    USE SIGNAL ;
    SHAPE ABUTMENT ;
    PORT
      LAYER met2 ;
      RECT 160.470 0.000 160.610 0.420 ;
    END
  END r0_rd_out[7]
  PIN r0_rd_out[8]
    DIRECTION OUTPUT ;
    USE SIGNAL ;
    SHAPE ABUTMENT ;
    PORT
      LAYER met2 ;
      RECT 163.690 0.000 163.830 0.420 ;
    END
  END r0_rd_out[8]
  PIN r0_rd_out[9]
    DIRECTION OUTPUT ;
    USE SIGNAL ;
    SHAPE ABUTMENT ;
    PORT
      LAYER met2 ;
      RECT 166.910 0.000 167.050 0.420 ;
    END
  END r0_rd_out[9]
  PIN r0_rd_out[10]
    DIRECTION OUTPUT ;
    USE SIGNAL ;
    SHAPE ABUTMENT ;
    PORT
      LAYER met2 ;
      RECT 170.130 0.000 170.270 0.420 ;
    END
  END r0_rd_out[10]
  PIN r0_rd_out[11]
    DIRECTION OUTPUT ;
    USE SIGNAL ;
    SHAPE ABUTMENT ;
    PORT
      LAYER met2 ;
      RECT 173.350 0.000 173.490 0.420 ;
    END
  END r0_rd_out[11]
  PIN r0_rd_out[12]
    DIRECTION OUTPUT ;
    USE SIGNAL ;
    SHAPE ABUTMENT ;
    PORT
      LAYER met2 ;
      RECT 176.570 0.000 176.710 0.420 ;
    END
  END r0_rd_out[12]
  PIN r0_rd_out[13]
    DIRECTION OUTPUT ;
    USE SIGNAL ;
    SHAPE ABUTMENT ;
    PORT
      LAYER met2 ;
      RECT 179.790 0.000 179.930 0.420 ;
    END
  END r0_rd_out[13]
  PIN r0_rd_out[14]
    DIRECTION OUTPUT ;
    USE SIGNAL ;
    SHAPE ABUTMENT ;
    PORT
      LAYER met2 ;
      RECT 183.010 0.000 183.150 0.420 ;
    END
  END r0_rd_out[14]
  PIN r0_rd_out[15]
    DIRECTION OUTPUT ;
    USE SIGNAL ;
    SHAPE ABUTMENT ;
    PORT
      LAYER met2 ;
      RECT 186.230 0.000 186.370 0.420 ;
    END
  END r0_rd_out[15]
  PIN r0_rd_out[16]
    DIRECTION OUTPUT ;
    USE SIGNAL ;
    SHAPE ABUTMENT ;
    PORT
      LAYER met2 ;
      RECT 189.450 0.000 189.590 0.420 ;
    END
  END r0_rd_out[16]
  PIN r0_rd_out[17]
    DIRECTION OUTPUT ;
    USE SIGNAL ;
    SHAPE ABUTMENT ;
    PORT
      LAYER met2 ;
      RECT 192.670 0.000 192.810 0.420 ;
    END
  END r0_rd_out[17]
  PIN r0_rd_out[18]
    DIRECTION OUTPUT ;
    USE SIGNAL ;
    SHAPE ABUTMENT ;
    PORT
      LAYER met2 ;
      RECT 195.890 0.000 196.030 0.420 ;
    END
  END r0_rd_out[18]
  PIN r0_rd_out[19]
    DIRECTION OUTPUT ;
    USE SIGNAL ;
    SHAPE ABUTMENT ;
    PORT
      LAYER met2 ;
      RECT 199.110 0.000 199.250 0.420 ;
    END
  END r0_rd_out[19]
  PIN r0_rd_out[20]
    DIRECTION OUTPUT ;
    USE SIGNAL ;
    SHAPE ABUTMENT ;
    PORT
      LAYER met2 ;
      RECT 202.330 0.000 202.470 0.420 ;
    END
  END r0_rd_out[20]
  PIN r0_rd_out[21]
    DIRECTION OUTPUT ;
    USE SIGNAL ;
    SHAPE ABUTMENT ;
    PORT
      LAYER met2 ;
      RECT 205.550 0.000 205.690 0.420 ;
    END
  END r0_rd_out[21]
  PIN r0_rd_out[22]
    DIRECTION OUTPUT ;
    USE SIGNAL ;
    SHAPE ABUTMENT ;
    PORT
      LAYER met2 ;
      RECT 208.770 0.000 208.910 0.420 ;
    END
  END r0_rd_out[22]
  PIN r0_rd_out[23]
    DIRECTION OUTPUT ;
    USE SIGNAL ;
    SHAPE ABUTMENT ;
    PORT
      LAYER met2 ;
      RECT 211.990 0.000 212.130 0.420 ;
    END
  END r0_rd_out[23]
  PIN r0_rd_out[24]
    DIRECTION OUTPUT ;
    USE SIGNAL ;
    SHAPE ABUTMENT ;
    PORT
      LAYER met2 ;
      RECT 215.210 0.000 215.350 0.420 ;
    END
  END r0_rd_out[24]
  PIN r0_rd_out[25]
    DIRECTION OUTPUT ;
    USE SIGNAL ;
    SHAPE ABUTMENT ;
    PORT
      LAYER met2 ;
      RECT 218.430 0.000 218.570 0.420 ;
    END
  END r0_rd_out[25]
  PIN r0_rd_out[26]
    DIRECTION OUTPUT ;
    USE SIGNAL ;
    SHAPE ABUTMENT ;
    PORT
      LAYER met2 ;
      RECT 221.650 0.000 221.790 0.420 ;
    END
  END r0_rd_out[26]
  PIN r0_rd_out[27]
    DIRECTION OUTPUT ;
    USE SIGNAL ;
    SHAPE ABUTMENT ;
    PORT
      LAYER met2 ;
      RECT 224.870 0.000 225.010 0.420 ;
    END
  END r0_rd_out[27]
  PIN r0_rd_out[28]
    DIRECTION OUTPUT ;
    USE SIGNAL ;
    SHAPE ABUTMENT ;
    PORT
      LAYER met2 ;
      RECT 228.090 0.000 228.230 0.420 ;
    END
  END r0_rd_out[28]
  PIN r0_rd_out[29]
    DIRECTION OUTPUT ;
    USE SIGNAL ;
    SHAPE ABUTMENT ;
    PORT
      LAYER met2 ;
      RECT 231.310 0.000 231.450 0.420 ;
    END
  END r0_rd_out[29]
  PIN r0_rd_out[30]
    DIRECTION OUTPUT ;
    USE SIGNAL ;
    SHAPE ABUTMENT ;
    PORT
      LAYER met2 ;
      RECT 234.530 0.000 234.670 0.420 ;
    END
  END r0_rd_out[30]
  PIN r0_rd_out[31]
    DIRECTION OUTPUT ;
    USE SIGNAL ;
    SHAPE ABUTMENT ;
    PORT
      LAYER met2 ;
      RECT 237.750 0.000 237.890 0.420 ;
    END
  END r0_rd_out[31]
  PIN r0_rd_out[32]
    DIRECTION OUTPUT ;
    USE SIGNAL ;
    SHAPE ABUTMENT ;
    PORT
      LAYER met2 ;
      RECT 240.970 0.000 241.110 0.420 ;
    END
  END r0_rd_out[32]
  PIN r0_rd_out[33]
    DIRECTION OUTPUT ;
    USE SIGNAL ;
    SHAPE ABUTMENT ;
    PORT
      LAYER met2 ;
      RECT 244.190 0.000 244.330 0.420 ;
    END
  END r0_rd_out[33]
  PIN r0_rd_out[34]
    DIRECTION OUTPUT ;
    USE SIGNAL ;
    SHAPE ABUTMENT ;
    PORT
      LAYER met2 ;
      RECT 247.410 0.000 247.550 0.420 ;
    END
  END r0_rd_out[34]
  PIN r0_rd_out[35]
    DIRECTION OUTPUT ;
    USE SIGNAL ;
    SHAPE ABUTMENT ;
    PORT
      LAYER met2 ;
      RECT 250.630 0.000 250.770 0.420 ;
    END
  END r0_rd_out[35]
  PIN r0_rd_out[36]
    DIRECTION OUTPUT ;
    USE SIGNAL ;
    SHAPE ABUTMENT ;
    PORT
      LAYER met2 ;
      RECT 253.850 0.000 253.990 0.420 ;
    END
  END r0_rd_out[36]
  PIN r0_rd_out[37]
    DIRECTION OUTPUT ;
    USE SIGNAL ;
    SHAPE ABUTMENT ;
    PORT
      LAYER met2 ;
      RECT 257.070 0.000 257.210 0.420 ;
    END
  END r0_rd_out[37]
  PIN r0_rd_out[38]
    DIRECTION OUTPUT ;
    USE SIGNAL ;
    SHAPE ABUTMENT ;
    PORT
      LAYER met2 ;
      RECT 260.290 0.000 260.430 0.420 ;
    END
  END r0_rd_out[38]
  PIN r0_rd_out[39]
    DIRECTION OUTPUT ;
    USE SIGNAL ;
    SHAPE ABUTMENT ;
    PORT
      LAYER met2 ;
      RECT 263.510 0.000 263.650 0.420 ;
    END
  END r0_rd_out[39]
  PIN r0_rd_out[40]
    DIRECTION OUTPUT ;
    USE SIGNAL ;
    SHAPE ABUTMENT ;
    PORT
      LAYER met2 ;
      RECT 266.730 0.000 266.870 0.420 ;
    END
  END r0_rd_out[40]
  PIN r0_rd_out[41]
    DIRECTION OUTPUT ;
    USE SIGNAL ;
    SHAPE ABUTMENT ;
    PORT
      LAYER met2 ;
      RECT 269.950 0.000 270.090 0.420 ;
    END
  END r0_rd_out[41]
  PIN r0_rd_out[42]
    DIRECTION OUTPUT ;
    USE SIGNAL ;
    SHAPE ABUTMENT ;
    PORT
      LAYER met2 ;
      RECT 273.170 0.000 273.310 0.420 ;
    END
  END r0_rd_out[42]
  PIN r0_rd_out[43]
    DIRECTION OUTPUT ;
    USE SIGNAL ;
    SHAPE ABUTMENT ;
    PORT
      LAYER met2 ;
      RECT 137.930 404.860 138.070 405.280 ;
    END
  END r0_rd_out[43]
  PIN r0_rd_out[44]
    DIRECTION OUTPUT ;
    USE SIGNAL ;
    SHAPE ABUTMENT ;
    PORT
      LAYER met2 ;
      RECT 141.150 404.860 141.290 405.280 ;
    END
  END r0_rd_out[44]
  PIN r0_rd_out[45]
    DIRECTION OUTPUT ;
    USE SIGNAL ;
    SHAPE ABUTMENT ;
    PORT
      LAYER met2 ;
      RECT 144.370 404.860 144.510 405.280 ;
    END
  END r0_rd_out[45]
  PIN r0_rd_out[46]
    DIRECTION OUTPUT ;
    USE SIGNAL ;
    SHAPE ABUTMENT ;
    PORT
      LAYER met2 ;
      RECT 147.590 404.860 147.730 405.280 ;
    END
  END r0_rd_out[46]
  PIN r0_rd_out[47]
    DIRECTION OUTPUT ;
    USE SIGNAL ;
    SHAPE ABUTMENT ;
    PORT
      LAYER met2 ;
      RECT 150.810 404.860 150.950 405.280 ;
    END
  END r0_rd_out[47]
  PIN r0_rd_out[48]
    DIRECTION OUTPUT ;
    USE SIGNAL ;
    SHAPE ABUTMENT ;
    PORT
      LAYER met2 ;
      RECT 154.030 404.860 154.170 405.280 ;
    END
  END r0_rd_out[48]
  PIN r0_rd_out[49]
    DIRECTION OUTPUT ;
    USE SIGNAL ;
    SHAPE ABUTMENT ;
    PORT
      LAYER met2 ;
      RECT 157.250 404.860 157.390 405.280 ;
    END
  END r0_rd_out[49]
  PIN r0_rd_out[50]
    DIRECTION OUTPUT ;
    USE SIGNAL ;
    SHAPE ABUTMENT ;
    PORT
      LAYER met2 ;
      RECT 160.470 404.860 160.610 405.280 ;
    END
  END r0_rd_out[50]
  PIN r0_rd_out[51]
    DIRECTION OUTPUT ;
    USE SIGNAL ;
    SHAPE ABUTMENT ;
    PORT
      LAYER met2 ;
      RECT 163.690 404.860 163.830 405.280 ;
    END
  END r0_rd_out[51]
  PIN r0_rd_out[52]
    DIRECTION OUTPUT ;
    USE SIGNAL ;
    SHAPE ABUTMENT ;
    PORT
      LAYER met2 ;
      RECT 166.910 404.860 167.050 405.280 ;
    END
  END r0_rd_out[52]
  PIN r0_rd_out[53]
    DIRECTION OUTPUT ;
    USE SIGNAL ;
    SHAPE ABUTMENT ;
    PORT
      LAYER met2 ;
      RECT 170.130 404.860 170.270 405.280 ;
    END
  END r0_rd_out[53]
  PIN r0_rd_out[54]
    DIRECTION OUTPUT ;
    USE SIGNAL ;
    SHAPE ABUTMENT ;
    PORT
      LAYER met2 ;
      RECT 173.350 404.860 173.490 405.280 ;
    END
  END r0_rd_out[54]
  PIN r0_rd_out[55]
    DIRECTION OUTPUT ;
    USE SIGNAL ;
    SHAPE ABUTMENT ;
    PORT
      LAYER met2 ;
      RECT 176.570 404.860 176.710 405.280 ;
    END
  END r0_rd_out[55]
  PIN r0_rd_out[56]
    DIRECTION OUTPUT ;
    USE SIGNAL ;
    SHAPE ABUTMENT ;
    PORT
      LAYER met2 ;
      RECT 179.790 404.860 179.930 405.280 ;
    END
  END r0_rd_out[56]
  PIN r0_rd_out[57]
    DIRECTION OUTPUT ;
    USE SIGNAL ;
    SHAPE ABUTMENT ;
    PORT
      LAYER met2 ;
      RECT 183.010 404.860 183.150 405.280 ;
    END
  END r0_rd_out[57]
  PIN r0_rd_out[58]
    DIRECTION OUTPUT ;
    USE SIGNAL ;
    SHAPE ABUTMENT ;
    PORT
      LAYER met2 ;
      RECT 186.230 404.860 186.370 405.280 ;
    END
  END r0_rd_out[58]
  PIN r0_rd_out[59]
    DIRECTION OUTPUT ;
    USE SIGNAL ;
    SHAPE ABUTMENT ;
    PORT
      LAYER met2 ;
      RECT 189.450 404.860 189.590 405.280 ;
    END
  END r0_rd_out[59]
  PIN r0_rd_out[60]
    DIRECTION OUTPUT ;
    USE SIGNAL ;
    SHAPE ABUTMENT ;
    PORT
      LAYER met2 ;
      RECT 192.670 404.860 192.810 405.280 ;
    END
  END r0_rd_out[60]
  PIN r0_rd_out[61]
    DIRECTION OUTPUT ;
    USE SIGNAL ;
    SHAPE ABUTMENT ;
    PORT
      LAYER met2 ;
      RECT 195.890 404.860 196.030 405.280 ;
    END
  END r0_rd_out[61]
  PIN r0_rd_out[62]
    DIRECTION OUTPUT ;
    USE SIGNAL ;
    SHAPE ABUTMENT ;
    PORT
      LAYER met2 ;
      RECT 199.110 404.860 199.250 405.280 ;
    END
  END r0_rd_out[62]
  PIN r0_rd_out[63]
    DIRECTION OUTPUT ;
    USE SIGNAL ;
    SHAPE ABUTMENT ;
    PORT
      LAYER met2 ;
      RECT 202.330 404.860 202.470 405.280 ;
    END
  END r0_rd_out[63]
  PIN r0_rd_out[64]
    DIRECTION OUTPUT ;
    USE SIGNAL ;
    SHAPE ABUTMENT ;
    PORT
      LAYER met2 ;
      RECT 205.550 404.860 205.690 405.280 ;
    END
  END r0_rd_out[64]
  PIN r0_rd_out[65]
    DIRECTION OUTPUT ;
    USE SIGNAL ;
    SHAPE ABUTMENT ;
    PORT
      LAYER met2 ;
      RECT 208.770 404.860 208.910 405.280 ;
    END
  END r0_rd_out[65]
  PIN r0_rd_out[66]
    DIRECTION OUTPUT ;
    USE SIGNAL ;
    SHAPE ABUTMENT ;
    PORT
      LAYER met2 ;
      RECT 211.990 404.860 212.130 405.280 ;
    END
  END r0_rd_out[66]
  PIN r0_rd_out[67]
    DIRECTION OUTPUT ;
    USE SIGNAL ;
    SHAPE ABUTMENT ;
    PORT
      LAYER met2 ;
      RECT 215.210 404.860 215.350 405.280 ;
    END
  END r0_rd_out[67]
  PIN r0_rd_out[68]
    DIRECTION OUTPUT ;
    USE SIGNAL ;
    SHAPE ABUTMENT ;
    PORT
      LAYER met2 ;
      RECT 218.430 404.860 218.570 405.280 ;
    END
  END r0_rd_out[68]
  PIN r0_rd_out[69]
    DIRECTION OUTPUT ;
    USE SIGNAL ;
    SHAPE ABUTMENT ;
    PORT
      LAYER met2 ;
      RECT 221.650 404.860 221.790 405.280 ;
    END
  END r0_rd_out[69]
  PIN r0_rd_out[70]
    DIRECTION OUTPUT ;
    USE SIGNAL ;
    SHAPE ABUTMENT ;
    PORT
      LAYER met2 ;
      RECT 224.870 404.860 225.010 405.280 ;
    END
  END r0_rd_out[70]
  PIN r0_rd_out[71]
    DIRECTION OUTPUT ;
    USE SIGNAL ;
    SHAPE ABUTMENT ;
    PORT
      LAYER met2 ;
      RECT 228.090 404.860 228.230 405.280 ;
    END
  END r0_rd_out[71]
  PIN r0_rd_out[72]
    DIRECTION OUTPUT ;
    USE SIGNAL ;
    SHAPE ABUTMENT ;
    PORT
      LAYER met2 ;
      RECT 231.310 404.860 231.450 405.280 ;
    END
  END r0_rd_out[72]
  PIN r0_rd_out[73]
    DIRECTION OUTPUT ;
    USE SIGNAL ;
    SHAPE ABUTMENT ;
    PORT
      LAYER met2 ;
      RECT 234.530 404.860 234.670 405.280 ;
    END
  END r0_rd_out[73]
  PIN r0_rd_out[74]
    DIRECTION OUTPUT ;
    USE SIGNAL ;
    SHAPE ABUTMENT ;
    PORT
      LAYER met2 ;
      RECT 237.750 404.860 237.890 405.280 ;
    END
  END r0_rd_out[74]
  PIN r0_rd_out[75]
    DIRECTION OUTPUT ;
    USE SIGNAL ;
    SHAPE ABUTMENT ;
    PORT
      LAYER met2 ;
      RECT 240.970 404.860 241.110 405.280 ;
    END
  END r0_rd_out[75]
  PIN r0_rd_out[76]
    DIRECTION OUTPUT ;
    USE SIGNAL ;
    SHAPE ABUTMENT ;
    PORT
      LAYER met2 ;
      RECT 244.190 404.860 244.330 405.280 ;
    END
  END r0_rd_out[76]
  PIN r0_rd_out[77]
    DIRECTION OUTPUT ;
    USE SIGNAL ;
    SHAPE ABUTMENT ;
    PORT
      LAYER met2 ;
      RECT 247.410 404.860 247.550 405.280 ;
    END
  END r0_rd_out[77]
  PIN r0_rd_out[78]
    DIRECTION OUTPUT ;
    USE SIGNAL ;
    SHAPE ABUTMENT ;
    PORT
      LAYER met2 ;
      RECT 250.630 404.860 250.770 405.280 ;
    END
  END r0_rd_out[78]
  PIN r0_rd_out[79]
    DIRECTION OUTPUT ;
    USE SIGNAL ;
    SHAPE ABUTMENT ;
    PORT
      LAYER met2 ;
      RECT 253.850 404.860 253.990 405.280 ;
    END
  END r0_rd_out[79]
  PIN r0_rd_out[80]
    DIRECTION OUTPUT ;
    USE SIGNAL ;
    SHAPE ABUTMENT ;
    PORT
      LAYER met2 ;
      RECT 257.070 404.860 257.210 405.280 ;
    END
  END r0_rd_out[80]
  PIN r0_rd_out[81]
    DIRECTION OUTPUT ;
    USE SIGNAL ;
    SHAPE ABUTMENT ;
    PORT
      LAYER met2 ;
      RECT 260.290 404.860 260.430 405.280 ;
    END
  END r0_rd_out[81]
  PIN r0_rd_out[82]
    DIRECTION OUTPUT ;
    USE SIGNAL ;
    SHAPE ABUTMENT ;
    PORT
      LAYER met2 ;
      RECT 263.510 404.860 263.650 405.280 ;
    END
  END r0_rd_out[82]
  PIN r0_rd_out[83]
    DIRECTION OUTPUT ;
    USE SIGNAL ;
    SHAPE ABUTMENT ;
    PORT
      LAYER met2 ;
      RECT 266.730 404.860 266.870 405.280 ;
    END
  END r0_rd_out[83]
  PIN r0_rd_out[84]
    DIRECTION OUTPUT ;
    USE SIGNAL ;
    SHAPE ABUTMENT ;
    PORT
      LAYER met2 ;
      RECT 269.950 404.860 270.090 405.280 ;
    END
  END r0_rd_out[84]
  PIN w0_addr_in[0]
    DIRECTION INPUT ;
    USE SIGNAL ;
    SHAPE ABUTMENT ;
    PORT
      LAYER met3 ;
      RECT 0.000 333.050 0.900 333.350 ;
    END
  END w0_addr_in[0]
  PIN w0_addr_in[1]
    DIRECTION INPUT ;
    USE SIGNAL ;
    SHAPE ABUTMENT ;
    PORT
      LAYER met3 ;
      RECT 0.000 340.530 0.900 340.830 ;
    END
  END w0_addr_in[1]
  PIN w0_addr_in[2]
    DIRECTION INPUT ;
    USE SIGNAL ;
    SHAPE ABUTMENT ;
    PORT
      LAYER met3 ;
      RECT 0.000 348.010 0.900 348.310 ;
    END
  END w0_addr_in[2]
  PIN w0_addr_in[3]
    DIRECTION INPUT ;
    USE SIGNAL ;
    SHAPE ABUTMENT ;
    PORT
      LAYER met3 ;
      RECT 298.560 318.090 299.460 318.390 ;
    END
  END w0_addr_in[3]
  PIN r0_addr_in[0]
    DIRECTION INPUT ;
    USE SIGNAL ;
    SHAPE ABUTMENT ;
    PORT
      LAYER met3 ;
      RECT 0.000 355.490 0.900 355.790 ;
    END
  END r0_addr_in[0]
  PIN r0_addr_in[1]
    DIRECTION INPUT ;
    USE SIGNAL ;
    SHAPE ABUTMENT ;
    PORT
      LAYER met3 ;
      RECT 0.000 362.970 0.900 363.270 ;
    END
  END r0_addr_in[1]
  PIN r0_addr_in[2]
    DIRECTION INPUT ;
    USE SIGNAL ;
    SHAPE ABUTMENT ;
    PORT
      LAYER met3 ;
      RECT 0.000 370.450 0.900 370.750 ;
    END
  END r0_addr_in[2]
  PIN r0_addr_in[3]
    DIRECTION INPUT ;
    USE SIGNAL ;
    SHAPE ABUTMENT ;
    PORT
      LAYER met3 ;
      RECT 298.560 340.530 299.460 340.830 ;
    END
  END r0_addr_in[3]
  PIN w0_we_in
    DIRECTION INPUT ;
    USE SIGNAL ;
    SHAPE ABUTMENT ;
    PORT
      LAYER met2 ;
      RECT 273.170 404.860 273.310 405.280 ;
    END
  END w0_we_in
  PIN w0_ce_in
    DIRECTION INPUT ;
    USE SIGNAL ;
    SHAPE ABUTMENT ;
    PORT
      LAYER met2 ;
      RECT 276.390 404.860 276.530 405.280 ;
    END
  END w0_ce_in
  PIN w0_clk
    DIRECTION INPUT ;
    USE SIGNAL ;
    SHAPE ABUTMENT ;
    PORT
      LAYER met2 ;
      RECT 279.610 404.860 279.750 405.280 ;
    END
  END w0_clk
  PIN r0_ce_in
    DIRECTION INPUT ;
    USE SIGNAL ;
    SHAPE ABUTMENT ;
    PORT
      LAYER met2 ;
      RECT 282.830 404.860 282.970 405.280 ;
    END
  END r0_ce_in
  PIN r0_clk
    DIRECTION INPUT ;
    USE SIGNAL ;
    SHAPE ABUTMENT ;
    PORT
      LAYER met2 ;
      RECT 286.050 404.860 286.190 405.280 ;
    END
  END r0_clk
  PIN VSS
    DIRECTION INOUT ;
    USE GROUND ;
    PORT
      LAYER met4 ;
      RECT 2.160 4.080 3.360 401.200 ;
      RECT 13.040 4.080 14.240 401.200 ;
      RECT 23.920 4.080 25.120 401.200 ;
      RECT 34.800 4.080 36.000 401.200 ;
      RECT 45.680 4.080 46.880 401.200 ;
      RECT 56.560 4.080 57.760 401.200 ;
      RECT 67.440 4.080 68.640 401.200 ;
      RECT 78.320 4.080 79.520 401.200 ;
      RECT 89.200 4.080 90.400 401.200 ;
      RECT 100.080 4.080 101.280 401.200 ;
      RECT 110.960 4.080 112.160 401.200 ;
      RECT 121.840 4.080 123.040 401.200 ;
      RECT 132.720 4.080 133.920 401.200 ;
      RECT 143.600 4.080 144.800 401.200 ;
      RECT 154.480 4.080 155.680 401.200 ;
      RECT 165.360 4.080 166.560 401.200 ;
      RECT 176.240 4.080 177.440 401.200 ;
      RECT 187.120 4.080 188.320 401.200 ;
      RECT 198.000 4.080 199.200 401.200 ;
      RECT 208.880 4.080 210.080 401.200 ;
      RECT 219.760 4.080 220.960 401.200 ;
      RECT 230.640 4.080 231.840 401.200 ;
      RECT 241.520 4.080 242.720 401.200 ;
      RECT 252.400 4.080 253.600 401.200 ;
      RECT 263.280 4.080 264.480 401.200 ;
      RECT 274.160 4.080 275.360 401.200 ;
      RECT 285.040 4.080 286.240 401.200 ;
      RECT 295.920 4.080 297.120 401.200 ;
    END
  END VSS
  PIN VDD
    DIRECTION INOUT ;
    USE POWER ;
    PORT
      LAYER met4 ;
      RECT 2.160 4.080 3.360 401.200 ;
      RECT 13.040 4.080 14.240 401.200 ;
      RECT 23.920 4.080 25.120 401.200 ;
      RECT 34.800 4.080 36.000 401.200 ;
      RECT 45.680 4.080 46.880 401.200 ;
      RECT 56.560 4.080 57.760 401.200 ;
      RECT 67.440 4.080 68.640 401.200 ;
      RECT 78.320 4.080 79.520 401.200 ;
      RECT 89.200 4.080 90.400 401.200 ;
      RECT 100.080 4.080 101.280 401.200 ;
      RECT 110.960 4.080 112.160 401.200 ;
      RECT 121.840 4.080 123.040 401.200 ;
      RECT 132.720 4.080 133.920 401.200 ;
      RECT 143.600 4.080 144.800 401.200 ;
      RECT 154.480 4.080 155.680 401.200 ;
      RECT 165.360 4.080 166.560 401.200 ;
      RECT 176.240 4.080 177.440 401.200 ;
      RECT 187.120 4.080 188.320 401.200 ;
      RECT 198.000 4.080 199.200 401.200 ;
      RECT 208.880 4.080 210.080 401.200 ;
      RECT 219.760 4.080 220.960 401.200 ;
      RECT 230.640 4.080 231.840 401.200 ;
      RECT 241.520 4.080 242.720 401.200 ;
      RECT 252.400 4.080 253.600 401.200 ;
      RECT 263.280 4.080 264.480 401.200 ;
      RECT 274.160 4.080 275.360 401.200 ;
      RECT 285.040 4.080 286.240 401.200 ;
      RECT 295.920 4.080 297.120 401.200 ;
    END
  END VDD
  OBS
    LAYER met1 ;
    RECT 0 0 299.460 405.280 ;
    LAYER met2 ;
    RECT 0 0 299.460 405.280 ;
    LAYER met3 ;
    RECT 0 0 299.460 405.280 ;
    LAYER met4 ;
    RECT 0 0 299.460 405.280 ;
  END
END fakeram_85x16_1r1w

END LIBRARY
